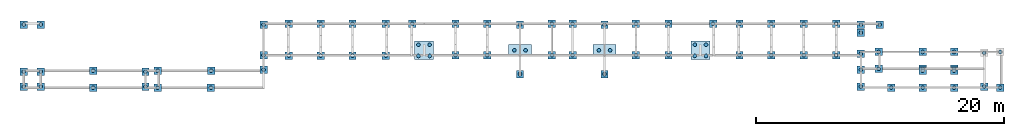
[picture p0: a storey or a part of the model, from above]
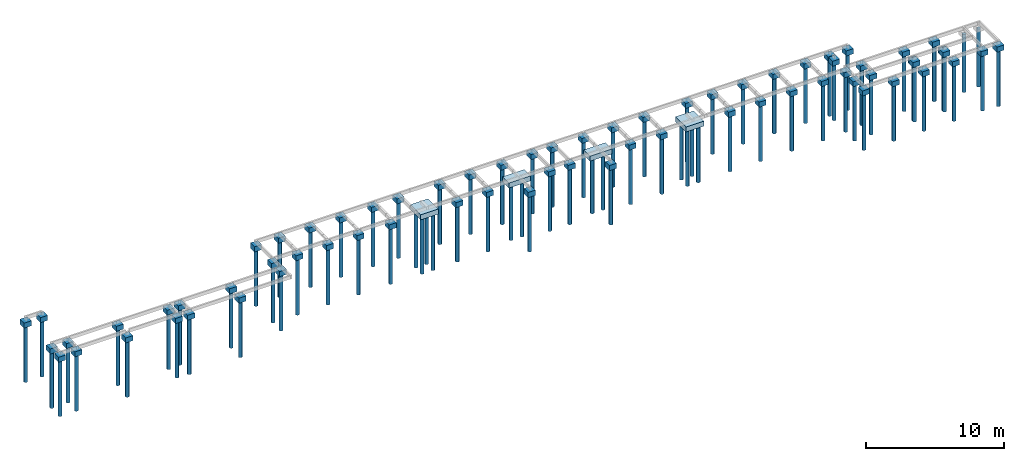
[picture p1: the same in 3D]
Properties of the parts of a building model (IFC4)

# File
Description: IFC4
Time: 2025-08-13T14:13:05
Made in: IfcPlusPlus

# IfcBuildingStorey (3)
Name | LongName | Elevation (cm)
Baldrame | Baldrame | -170
Arquibancada | Arquibancada | 0
Respalto | Respalto | 280

# IfcBeam (379)
Material: Concreto
Pset_ConcreteElementGeneral - ConcreteCover: 3 cm; ConstructionMethod: InSitu; ExposureClass: 2; StrengthClass: C-25
AltoQi_Eberick_Elemento - Elemento: Viga; Tipo: retangular; Taxa de armadura: Não calculado
AltoQi_Eberick_Padrão - Ambiente: Externo; Cobrimento: 3 cm; Classe de concreto: C-25
AltoQi_Eberick_Cargas - Cargas de parede (G2): 0; Adicional (G2): 0; Solo (S): 0; Acidental (Q): 0; Água (A): 0; Subpressão (AS): 0
Pset_BeamCommon - IsExternal: yes; LoadBearing: yes
Name | In | Seção_bw (cm) | Seção_h (cm) | Elevação (cm) | Reference
V1 | Baldrame | 14 | 30 | 0 | Viga C-25 - Seção Retangular 14 X 30
V10 | Baldrame | 14 | 30 | 0 | Viga C-25 - Seção Retangular 14 X 30
4 x V11 | Baldrame | 14 | 30 | 0 | Viga C-25 - Seção Retangular 14 X 30
6 x V12 | Baldrame | 14 | 30 | 0 | Viga C-25 - Seção Retangular 14 X 30
4 x V13 | Baldrame | 14 | 30 | 0 | Viga C-25 - Seção Retangular 14 X 30
6 x V14 | Baldrame | 14 | 30 | 0 | Viga C-25 - Seção Retangular 14 X 30
5 x V15 | Baldrame | 14 | 30 | 0 | Viga C-25 - Seção Retangular 14 X 30
V16 | Baldrame | 14 | 30 | 0 | Viga C-25 - Seção Retangular 14 X 30
V17 | Baldrame | 14 | 30 | 0 | Viga C-25 - Seção Retangular 14 X 30
V18 | Baldrame | 14 | 30 | 0 | Viga C-25 - Seção Retangular 14 X 30
V19 | Baldrame | 14 | 30 | 0 | Viga C-25 - Seção Retangular 14 X 30
6 x V2 | Baldrame | 14 | 30 | 0 | Viga C-25 - Seção Retangular 14 X 30
3 x V20 | Baldrame | 14 | 30 | 0 | Viga C-25 - Seção Retangular 14 X 30
3 x V21 | Baldrame | 19 | 30 | 0 | Viga C-25 - Seção Retangular 19 X 30
3 x V22 | Baldrame | 19 | 19 | 0 | Viga C-25 - Seção Retangular 19 X 19
3 x V23 | Baldrame | 19 | 19 | 0 | Viga C-25 - Seção Retangular 19 X 19
3 x V24 | Baldrame | 19 | 30 | 0 | Viga C-25 - Seção Retangular 19 X 30
3 x V25 | Baldrame | 19 | 30 | 0 | Viga C-25 - Seção Retangular 19 X 30
3 x V26 | Baldrame | 19 | 30 | 0 | Viga C-25 - Seção Retangular 19 X 30
3 x V27 | Baldrame | 19 | 30 | 0 | Viga C-25 - Seção Retangular 19 X 30
2 x V28 | Baldrame | 14 | 30 | 0 | Viga C-25 - Seção Retangular 14 X 30
V29 | Baldrame | 14 | 30 | 0 | Viga C-25 - Seção Retangular 14 X 30
8 x V3 | Baldrame | 14 | 30 | 0 | Viga C-25 - Seção Retangular 14 X 30
V30 | Baldrame | 14 | 30 | 0 | Viga C-25 - Seção Retangular 14 X 30
2 x V31 | Baldrame | 14 | 30 | 0 | Viga C-25 - Seção Retangular 14 X 30
3 x V32 | Baldrame | 19 | 30 | 0 | Viga C-25 - Seção Retangular 19 X 30
3 x V33 | Baldrame | 19 | 30 | 0 | Viga C-25 - Seção Retangular 19 X 30
3 x V34 | Baldrame | 19 | 30 | 0 | Viga C-25 - Seção Retangular 19 X 30
3 x V35 | Baldrame | 19 | 30 | 0 | Viga C-25 - Seção Retangular 19 X 30
3 x V36 | Baldrame | 19 | 30 | 0 | Viga C-25 - Seção Retangular 19 X 30
3 x V37 | Baldrame | 19 | 30 | 0 | Viga C-25 - Seção Retangular 19 X 30
3 x V38 | Baldrame | 19 | 30 | 0 | Viga C-25 - Seção Retangular 19 X 30
2 x V39 | Baldrame | 14 | 30 | 0 | Viga C-25 - Seção Retangular 14 X 30
6 x V4 | Baldrame | 14 | 30 | 0 | Viga C-25 - Seção Retangular 14 X 30
V40 | Baldrame | 14 | 30 | 0 | Viga C-25 - Seção Retangular 14 X 30
2 x V41 | Baldrame | 14 | 30 | 0 | Viga C-25 - Seção Retangular 14 X 30
V42 | Baldrame | 14 | 30 | 0 | Viga C-25 - Seção Retangular 14 X 30
V5 | Baldrame | 14 | 30 | 0 | Viga C-25 - Seção Retangular 14 X 30
6 x V6 | Baldrame | 14 | 30 | 0 | Viga C-25 - Seção Retangular 14 X 30
3 x V7 | Baldrame | 14 | 30 | 0 | Viga C-25 - Seção Retangular 14 X 30
6 x V8 | Baldrame | 14 | 30 | 0 | Viga C-25 - Seção Retangular 14 X 30
6 x V9 | Baldrame | 14 | 30 | 0 | Viga C-25 - Seção Retangular 14 X 30
3 x V1 | Arquibancada | 14 | 30 | 0 | Viga C-25 - Seção Retangular 14 X 30
6 x V10 | Arquibancada | 14 | 30 | 0 | Viga C-25 - Seção Retangular 14 X 30
2 x V100 | Arquibancada | 14 | 30 | 0 | Viga C-25 - Seção Retangular 14 X 30
2 x V101 | Arquibancada | 14 | 30 | 0 | Viga C-25 - Seção Retangular 14 X 30
2 x V102 | Arquibancada | 14 | 30 | 0 | Viga C-25 - Seção Retangular 14 X 30
3 x V103 | Arquibancada | 14 | 30 | 0 | Viga C-25 - Seção Retangular 14 X 30
2 x V104 | Arquibancada | 14 | 30 | 0 | Viga C-25 - Seção Retangular 14 X 30
2 x V105 | Arquibancada | 14 | 30 | 0 | Viga C-25 - Seção Retangular 14 X 30
2 x V106 | Arquibancada | 14 | 30 | 0 | Viga C-25 - Seção Retangular 14 X 30
3 x V107 | Arquibancada | 14 | 30 | 0 | Viga C-25 - Seção Retangular 14 X 30
V11 | Arquibancada | 14 | 30 | 0 | Viga C-25 - Seção Retangular 14 X 30
V12 | Arquibancada | 14 | 30 | 0 | Viga C-25 - Seção Retangular 14 X 30
V13 | Arquibancada | 14 | 30 | 0 | Viga C-25 - Seção Retangular 14 X 30
V14 | Arquibancada | 14 | 30 | 0 | Viga C-25 - Seção Retangular 14 X 30
3 x V17 | Arquibancada | 14 | 30 | 0 | Viga C-25 - Seção Retangular 14 X 30
3 x V18 | Arquibancada | 14 | 30 | 0 | Viga C-25 - Seção Retangular 14 X 30
3 x V19 | Arquibancada | 14 | 30 | 0 | Viga C-25 - Seção Retangular 14 X 30
3 x V2 | Arquibancada | 14 | 30 | 0 | Viga C-25 - Seção Retangular 14 X 30
V20 | Arquibancada | 14 | 30 | 0 | Viga C-25 - Seção Retangular 14 X 30
6 x V21 | Arquibancada | 14 | 30 | 0 | Viga C-25 - Seção Retangular 14 X 30
3 x V22 | Arquibancada | 14 | 30 | 0 | Viga C-25 - Seção Retangular 14 X 30
3 x V23 | Arquibancada | 14 | 30 | 0 | Viga C-25 - Seção Retangular 14 X 30
6 x V24 | Arquibancada | 14 | 30 | 0 | Viga C-25 - Seção Retangular 14 X 30
V25 | Arquibancada | 14 | 30 | -13 | Viga C-25 - Seção Retangular 14 X 30
V26 | Arquibancada | 14 | 30 | -13 | Viga C-25 - Seção Retangular 14 X 30
V27 | Arquibancada | 14 | 30 | -13 | Viga C-25 - Seção Retangular 14 X 30
V28 | Arquibancada | 14 | 30 | -13 | Viga C-25 - Seção Retangular 14 X 30
3 x V29 | Arquibancada | 14 | 30 | 0 | Viga C-25 - Seção Retangular 14 X 30
9 x V3 | Arquibancada | 14 | 30 | 0 | Viga C-25 - Seção Retangular 14 X 30
5 x V31 | Arquibancada | 14 | 30 | 0 | Viga C-25 - Seção Retangular 14 X 30
V32 | Arquibancada | 14 | 30 | -13 | Viga C-25 - Seção Retangular 14 X 30
V33 | Arquibancada | 14 | 30 | -13 | Viga C-25 - Seção Retangular 14 X 30
3 x V35 | Arquibancada | 14 | 30 | 0 | Viga C-25 - Seção Retangular 14 X 30
3 x V36 | Arquibancada | 14 | 30 | 0 | Viga C-25 - Seção Retangular 14 X 30
9 x V37 | Arquibancada | 14 | 30 | 0 | Viga C-25 - Seção Retangular 14 X 30
9 x V38 | Arquibancada | 14 | 30 | 0 | Viga C-25 - Seção Retangular 14 X 30
V39 | Arquibancada | 14 | 30 | 12 | Viga C-25 - Seção Retangular 14 X 30
V4 | Arquibancada | 14 | 30 | 0 | Viga C-25 - Seção Retangular 14 X 30
V40 | Arquibancada | 14 | 30 | 12 | Viga C-25 - Seção Retangular 14 X 30
5 x V41 | Arquibancada | 14 | 30 | 0 | Viga C-25 - Seção Retangular 14 X 30
2 x V42 | Arquibancada | 14 | 30 | 0 | Viga C-25 - Seção Retangular 14 X 30
3 x V43 | Arquibancada | 14 | 30 | 0 | Viga C-25 - Seção Retangular 14 X 30
3 x V44 | Arquibancada | 14 | 20 | 0 | Viga C-25 - Seção Retangular 14 X 20
3 x V45 | Arquibancada | 14 | 30 | 0 | Viga C-25 - Seção Retangular 14 X 30
3 x V46 | Arquibancada | 14 | 30 | 12 | Viga C-25 - Seção Retangular 14 X 30
V47 | Arquibancada | 14 | 30 | 12 | Viga C-25 - Seção Retangular 14 X 30
V48 | Arquibancada | 14 | 30 | 12 | Viga C-25 - Seção Retangular 14 X 30
V49 | Arquibancada | 14 | 30 | 12 | Viga C-25 - Seção Retangular 14 X 30
4 x V5 | Arquibancada | 14 | 30 | 0 | Viga C-25 - Seção Retangular 14 X 30
3 x V50 | Arquibancada | 14 | 30 | 0 | Viga C-25 - Seção Retangular 14 X 30
3 x V51 | Arquibancada | 14 | 30 | 0 | Viga C-25 - Seção Retangular 14 X 30
8 x V52 | Arquibancada | 14 | 30 | 0 | Viga C-25 - Seção Retangular 14 X 30
8 x V53 | Arquibancada | 14 | 30 | 0 | Viga C-25 - Seção Retangular 14 X 30
V54 | Arquibancada | 14 | 30 | -19 | Viga C-25 - Seção Retangular 14 X 30
V55 | Arquibancada | 14 | 30 | -6 | Viga C-25 - Seção Retangular 14 X 30
V56 | Arquibancada | 14 | 30 | -19 | Viga C-25 - Seção Retangular 14 X 30
V57 | Arquibancada | 14 | 30 | -6 | Viga C-25 - Seção Retangular 14 X 30
V58 | Arquibancada | 14 | 30 | -6 | Viga C-25 - Seção Retangular 14 X 30
V59 | Arquibancada | 14 | 30 | -6 | Viga C-25 - Seção Retangular 14 X 30
2 x V6 | Arquibancada | 14 | 30 | 0 | Viga C-25 - Seção Retangular 14 X 30
4 x V60 | Arquibancada | 14 | 30 | 0 | Viga C-25 - Seção Retangular 14 X 30
3 x V61 | Arquibancada | 14 | 30 | 0 | Viga C-25 - Seção Retangular 14 X 30
3 x V62 | Arquibancada | 14 | 30 | 0 | Viga C-25 - Seção Retangular 14 X 30
V63 | Arquibancada | 14 | 30 | -19 | Viga C-25 - Seção Retangular 14 X 30
3 x V64 | Arquibancada | 14 | 30 | 0 | Viga C-25 - Seção Retangular 14 X 30
V66 | Arquibancada | 14 | 30 | -6 | Viga C-25 - Seção Retangular 14 X 30
V67 | Arquibancada | 14 | 30 | -6 | Viga C-25 - Seção Retangular 14 X 30
V68 | Arquibancada | 14 | 30 | -19 | Viga C-25 - Seção Retangular 14 X 30
V69 | Arquibancada | 14 | 30 | -19 | Viga C-25 - Seção Retangular 14 X 30
V7 | Arquibancada | 14 | 30 | 0 | Viga C-25 - Seção Retangular 14 X 30
V70 | Arquibancada | 14 | 30 | -19 | Viga C-25 - Seção Retangular 14 X 30
V71 | Arquibancada | 14 | 30 | -19 | Viga C-25 - Seção Retangular 14 X 30
V72 | Arquibancada | 14 | 30 | -19 | Viga C-25 - Seção Retangular 14 X 30
V73 | Arquibancada | 14 | 30 | -19 | Viga C-25 - Seção Retangular 14 X 30
V74 | Arquibancada | 14 | 30 | 0 | Viga C-25 - Seção Retangular 14 X 30
V75 | Arquibancada | 14 | 30 | -19 | Viga C-25 - Seção Retangular 14 X 30
V76 | Arquibancada | 14 | 30 | -19 | Viga C-25 - Seção Retangular 14 X 30
V77 | Arquibancada | 14 | 30 | 0 | Viga C-25 - Seção Retangular 14 X 30
V78 | Arquibancada | 14 | 30 | 0 | Viga C-25 - Seção Retangular 14 X 30
V8 | Arquibancada | 14 | 30 | 0 | Viga C-25 - Seção Retangular 14 X 30
V81 | Arquibancada | 14 | 30 | -19 | Viga C-25 - Seção Retangular 14 X 30
3 x V82 | Arquibancada | 14 | 30 | 0 | Viga C-25 - Seção Retangular 14 X 30
V83 | Arquibancada | 14 | 30 | -19 | Viga C-25 - Seção Retangular 14 X 30
V84 | Arquibancada | 14 | 30 | -19 | Viga C-25 - Seção Retangular 14 X 30
2 x V85 | Arquibancada | 14 | 30 | 0 | Viga C-25 - Seção Retangular 14 X 30
2 x V86 | Arquibancada | 14 | 30 | 0 | Viga C-25 - Seção Retangular 14 X 30
2 x V87 | Arquibancada | 14 | 30 | 0 | Viga C-25 - Seção Retangular 14 X 30
V88 | Arquibancada | 14 | 30 | 0 | Viga C-25 - Seção Retangular 14 X 30
3 x V89 | Arquibancada | 14 | 30 | 0 | Viga C-25 - Seção Retangular 14 X 30
2 x V9 | Arquibancada | 14 | 30 | 0 | Viga C-25 - Seção Retangular 14 X 30
2 x V90 | Arquibancada | 14 | 30 | 0 | Viga C-25 - Seção Retangular 14 X 30
2 x V91 | Arquibancada | 14 | 30 | 0 | Viga C-25 - Seção Retangular 14 X 30
2 x V92 | Arquibancada | 14 | 30 | 0 | Viga C-25 - Seção Retangular 14 X 30
2 x V93 | Arquibancada | 14 | 30 | 0 | Viga C-25 - Seção Retangular 14 X 30
2 x V94 | Arquibancada | 14 | 30 | 0 | Viga C-25 - Seção Retangular 14 X 30
3 x V95 | Arquibancada | 14 | 30 | 0 | Viga C-25 - Seção Retangular 14 X 30
2 x V96 | Arquibancada | 14 | 30 | 0 | Viga C-25 - Seção Retangular 14 X 30
2 x V97 | Arquibancada | 14 | 30 | 0 | Viga C-25 - Seção Retangular 14 X 30
2 x V98 | Arquibancada | 14 | 30 | 0 | Viga C-25 - Seção Retangular 14 X 30
3 x V99 | Arquibancada | 14 | 30 | 0 | Viga C-25 - Seção Retangular 14 X 30
3 x V1 | Respalto | 14 | 30 | 0 | Viga C-25 - Seção Retangular 14 X 30
3 x V2 | Respalto | 14 | 30 | 0 | Viga C-25 - Seção Retangular 14 X 30
2 x V3 | Respalto | 14 | 30 | 0 | Viga C-25 - Seção Retangular 14 X 30
V4 | Respalto | 14 | 30 | 0 | Viga C-25 - Seção Retangular 14 X 30
V5 | Respalto | 14 | 30 | 0 | Viga C-25 - Seção Retangular 14 X 30
2 x V6 | Respalto | 14 | 30 | 0 | Viga C-25 - Seção Retangular 14 X 30

# IfcColumn (193)
Material: Concreto
Pset_ConcreteElementGeneral - ConcreteCover: 3 cm; ConstructionMethod: InSitu; ExposureClass: 2; StrengthClass: C-25
AltoQi_Eberick_Elemento - Elemento: Pilar; Tipo: retangular; Taxa de armadura: Não calculado; Taxa de compressão bruta: Não calculado; Taxa de compressão homogeneizada: Não calculado
AltoQi_Eberick_Padrão - Ambiente: Externo; Cobrimento: 3 cm; Classe de concreto: C-25
Pset_ColumnCommon - IsExternal: yes; LoadBearing: yes
Name | In | Seção_b (cm) | Seção_h (cm) | Elevação (cm) | Reference
P1 | Baldrame | 14 | 30 | 0 | Pilar C-25 - Retangular 14x30
P10 | Baldrame | 14 | 30 | 0 | Pilar C-25 - Retangular 14x30
P100 | Baldrame | 14 | 30 | 0 | Pilar C-25 - Retangular 14x30
P101 | Baldrame | 14 | 30 | 0 | Pilar C-25 - Retangular 14x30
P102 | Baldrame | 14 | 30 | 0 | Pilar C-25 - Retangular 14x30
P103 | Baldrame | 14 | 30 | 0 | Pilar C-25 - Retangular 14x30
P104 | Baldrame | 14 | 30 | 0 | Pilar C-25 - Retangular 14x30
P105 | Baldrame | 14 | 30 | 0 | Pilar C-25 - Retangular 14x30
P106 | Baldrame | 14 | 30 | -19 | Pilar C-25 - Retangular 14x30
P11 | Baldrame | 14 | 30 | 0 | Pilar C-25 - Retangular 14x30
P12 | Baldrame | 14 | 30 | 0 | Pilar C-25 - Retangular 14x30
P13 | Baldrame | 14 | 30 | 0 | Pilar C-25 - Retangular 14x30
P14 | Baldrame | 14 | 30 | 0 | Pilar C-25 - Retangular 14x30
P15 | Baldrame | 14 | 30 | 0 | Pilar C-25 - Retangular 14x30
P16 | Baldrame | 14 | 30 | 0 | Pilar C-25 - Retangular 14x30
P17 | Baldrame | 14 | 30 | 0 | Pilar C-25 - Retangular 14x30
P18 | Baldrame | 14 | 30 | 0 | Pilar C-25 - Retangular 14x30
P19 | Baldrame | 14 | 30 | 0 | Pilar C-25 - Retangular 14x30
P2 | Baldrame | 14 | 30 | 0 | Pilar C-25 - Retangular 14x30
P20 | Baldrame | 14 | 30 | 0 | Pilar C-25 - Retangular 14x30
P21 | Baldrame | 19 | 19 | 0 | Pilar C-25 - Retangular 19x19
P22 | Baldrame | 14 | 30 | 0 | Pilar C-25 - Retangular 14x30
P23 | Baldrame | 14 | 30 | 0 | Pilar C-25 - Retangular 14x30
P3 | Baldrame | 14 | 30 | 0 | Pilar C-25 - Retangular 14x30
P38 | Baldrame | 14 | 30 | 0 | Pilar C-25 - Retangular 14x30
P4 | Baldrame | 14 | 30 | 0 | Pilar C-25 - Retangular 14x30
P44 | Baldrame | 20 | 93 | 0 | Pilar C-25 - Retangular 20x93
P47 | Baldrame | 14 | 93 | 0 | Pilar C-25 - Retangular 14x93
P48 | Baldrame | 14 | 93 | 0 | Pilar C-25 - Retangular 14x93
P5 | Baldrame | 14 | 30 | 0 | Pilar C-25 - Retangular 14x30
P51 | Baldrame | 20 | 93 | 0 | Pilar C-25 - Retangular 20x93
P57 | Baldrame | 14 | 30 | 0 | Pilar C-25 - Retangular 14x30
P58 | Baldrame | 19 | 30 | 0 | Pilar C-25 - Retangular 19x30
P59 | Baldrame | 19 | 30 | 0 | Pilar C-25 - Retangular 19x30
P6 | Baldrame | 14 | 30 | 0 | Pilar C-25 - Retangular 14x30
P60 | Baldrame | 19 | 30 | 0 | Pilar C-25 - Retangular 19x30
P61 | Baldrame | 19 | 30 | 0 | Pilar C-25 - Retangular 19x30
P62 | Baldrame | 14 | 30 | 0 | Pilar C-25 - Retangular 14x30
P63 | Baldrame | 14 | 30 | 0 | Pilar C-25 - Retangular 14x30
P64 | Baldrame | 14 | 30 | 0 | Pilar C-25 - Retangular 14x30
P65 | Baldrame | 14 | 30 | 0 | Pilar C-25 - Retangular 14x30
P66 | Baldrame | 14 | 30 | 0 | Pilar C-25 - Retangular 14x30
P67 | Baldrame | 14 | 30 | 0 | Pilar C-25 - Retangular 14x30
P68 | Baldrame | 14 | 30 | 0 | Pilar C-25 - Retangular 14x30
P69 | Baldrame | 14 | 30 | 0 | Pilar C-25 - Retangular 14x30
P7 | Baldrame | 14 | 30 | 0 | Pilar C-25 - Retangular 14x30
P70 | Baldrame | 14 | 30 | 0 | Pilar C-25 - Retangular 14x30
P71 | Baldrame | 19 | 19 | 0 | Pilar C-25 - Retangular 19x19
P72 | Baldrame | 14 | 40 | 0 | Pilar C-25 - Retangular 14x40
P73 | Baldrame | 14 | 30 | 0 | Pilar C-25 - Retangular 14x30
P74 | Baldrame | 14 | 30 | 0 | Pilar C-25 - Retangular 14x30
P75 | Baldrame | 14 | 30 | 0 | Pilar C-25 - Retangular 14x30
P76 | Baldrame | 14 | 30 | 0 | Pilar C-25 - Retangular 14x30
P77 | Baldrame | 14 | 30 | 0 | Pilar C-25 - Retangular 14x30
P78 | Baldrame | 14 | 30 | 0 | Pilar C-25 - Retangular 14x30
P79 | Baldrame | 14 | 30 | 0 | Pilar C-25 - Retangular 14x30
P8 | Baldrame | 14 | 30 | 0 | Pilar C-25 - Retangular 14x30
P80 | Baldrame | 14 | 30 | 0 | Pilar C-25 - Retangular 14x30
P81 | Baldrame | 14 | 30 | 0 | Pilar C-25 - Retangular 14x30
P82 | Baldrame | 14 | 30 | 0 | Pilar C-25 - Retangular 14x30
P83 | Baldrame | 14 | 30 | 0 | Pilar C-25 - Retangular 14x30
P84 | Baldrame | 14 | 30 | 0 | Pilar C-25 - Retangular 14x30
P85 | Baldrame | 14 | 30 | 0 | Pilar C-25 - Retangular 14x30
P86 | Baldrame | 14 | 30 | 0 | Pilar C-25 - Retangular 14x30
P87 | Baldrame | 14 | 29 | 0 | Pilar C-25 - Retangular 14x29
P88 | Baldrame | 14 | 30 | 0 | Pilar C-25 - Retangular 14x30
P89 | Baldrame | 14 | 30 | 0 | Pilar C-25 - Retangular 14x30
P9 | Baldrame | 14 | 30 | 0 | Pilar C-25 - Retangular 14x30
P90 | Baldrame | 14 | 30 | 0 | Pilar C-25 - Retangular 14x30
P91 | Baldrame | 14 | 30 | 0 | Pilar C-25 - Retangular 14x30
P92 | Baldrame | 14 | 30 | 0 | Pilar C-25 - Retangular 14x30
P93 | Baldrame | 14 | 30 | 0 | Pilar C-25 - Retangular 14x30
P94 | Baldrame | 14 | 30 | 0 | Pilar C-25 - Retangular 14x30
P96 | Baldrame | 14 | 30 | 0 | Pilar C-25 - Retangular 14x30
P97 | Baldrame | 14 | 30 | 0 | Pilar C-25 - Retangular 14x30
P98 | Baldrame | 14 | 30 | 0 | Pilar C-25 - Retangular 14x30
P10 | Arquibancada | 14 | 30 | 0 | Pilar C-25 - Retangular 14x30
P100 | Arquibancada | 14 | 30 | 0 | Pilar C-25 - Retangular 14x30
P101 | Arquibancada | 14 | 30 | 0 | Pilar C-25 - Retangular 14x30
P102 | Arquibancada | 14 | 30 | 0 | Pilar C-25 - Retangular 14x30
P103 | Arquibancada | 14 | 30 | 0 | Pilar C-25 - Retangular 14x30
P104 | Arquibancada | 14 | 30 | 12 | Pilar C-25 - Retangular 14x30
P105 | Arquibancada | 14 | 30 | 12 | Pilar C-25 - Retangular 14x30
P106 | Arquibancada | 14 | 30 | -10 | Pilar C-25 - Retangular 14x30
P107 | Arquibancada | 14 | 30 | 0 | Pilar C-25 - Retangular 14x30
P108 | Arquibancada | 14 | 30 | 0 | Pilar C-25 - Retangular 14x30
P109 | Arquibancada | 14 | 30 | -35 | Pilar C-25 - Retangular 14x30
P11 | Arquibancada | 14 | 30 | 0 | Pilar C-25 - Retangular 14x30
P12 | Arquibancada | 14 | 30 | 0 | Pilar C-25 - Retangular 14x30
P13 | Arquibancada | 14 | 30 | 0 | Pilar C-25 - Retangular 14x30
P14 | Arquibancada | 14 | 30 | 0 | Pilar C-25 - Retangular 14x30
P15 | Arquibancada | 14 | 30 | 0 | Pilar C-25 - Retangular 14x30
P16 | Arquibancada | 14 | 30 | 0 | Pilar C-25 - Retangular 14x30
P17 | Arquibancada | 14 | 30 | 0 | Pilar C-25 - Retangular 14x30
P18 | Arquibancada | 14 | 30 | 0 | Pilar C-25 - Retangular 14x30
P19 | Arquibancada | 14 | 30 | 0 | Pilar C-25 - Retangular 14x30
P20 | Arquibancada | 14 | 30 | 0 | Pilar C-25 - Retangular 14x30
P21 | Arquibancada | 19 | 19 | 0 | Pilar C-25 - Retangular 19x19
P22 | Arquibancada | 14 | 30 | 0 | Pilar C-25 - Retangular 14x30
P24 | Arquibancada | 19 | 19 | 0 | Pilar C-25 - Retangular 19x19
P25 | Arquibancada | 20 | 20 | 0 | Pilar C-25 - Retangular 20x20
P26 | Arquibancada | 19 | 19 | 0 | Pilar C-25 - Retangular 19x19
P27 | Arquibancada | 19 | 19 | 0 | Pilar C-25 - Retangular 19x19
P28 | Arquibancada | 19 | 19 | 0 | Pilar C-25 - Retangular 19x19
P29 | Arquibancada | 19 | 19 | 0 | Pilar C-25 - Retangular 19x19
P3 | Arquibancada | 14 | 30 | 0 | Pilar C-25 - Retangular 14x30
P30 | Arquibancada | 19 | 19 | 0 | Pilar C-25 - Retangular 19x19
P31 | Arquibancada | 19 | 19 | 0 | Pilar C-25 - Retangular 19x19
P32 | Arquibancada | 19 | 19 | 0 | Pilar C-25 - Retangular 19x19
P33 | Arquibancada | 19 | 19 | 0 | Pilar C-25 - Retangular 19x19
P34 | Arquibancada | 19 | 19 | 0 | Pilar C-25 - Retangular 19x19
P35 | Arquibancada | 19 | 19 | 0 | Pilar C-25 - Retangular 19x19
P36 | Arquibancada | 19 | 19 | 0 | Pilar C-25 - Retangular 19x19
P37 | Arquibancada | 19 | 19 | 0 | Pilar C-25 - Retangular 19x19
P38 | Arquibancada | 14 | 30 | 0 | Pilar C-25 - Retangular 14x30
P39 | Arquibancada | 19 | 19 | 0 | Pilar C-25 - Retangular 19x19
P4 | Arquibancada | 14 | 30 | 0 | Pilar C-25 - Retangular 14x30
P40 | Arquibancada | 20 | 20 | 0 | Pilar C-25 - Retangular 20x20
P41 | Arquibancada | 19 | 19 | 0 | Pilar C-25 - Retangular 19x19
P42 | Arquibancada | 19 | 19 | 0 | Pilar C-25 - Retangular 19x19
P43 | Arquibancada | 19 | 19 | 0 | Pilar C-25 - Retangular 19x19
P44 | Arquibancada | 20 | 93 | 0 | Pilar C-25 - Retangular 20x93
P45 | Arquibancada | 19 | 19 | 0 | Pilar C-25 - Retangular 19x19
P46 | Arquibancada | 19 | 19 | 0 | Pilar C-25 - Retangular 19x19
P47 | Arquibancada | 14 | 93 | 0 | Pilar C-25 - Retangular 14x93
P48 | Arquibancada | 14 | 93 | 0 | Pilar C-25 - Retangular 14x93
P49 | Arquibancada | 19 | 19 | 0 | Pilar C-25 - Retangular 19x19
P5 | Arquibancada | 14 | 30 | 0 | Pilar C-25 - Retangular 14x30
P50 | Arquibancada | 19 | 19 | 0 | Pilar C-25 - Retangular 19x19
P51 | Arquibancada | 20 | 93 | 0 | Pilar C-25 - Retangular 20x93
P52 | Arquibancada | 19 | 19 | 0 | Pilar C-25 - Retangular 19x19
P53 | Arquibancada | 19 | 19 | 0 | Pilar C-25 - Retangular 19x19
P54 | Arquibancada | 19 | 19 | 0 | Pilar C-25 - Retangular 19x19
P55 | Arquibancada | 19 | 19 | 0 | Pilar C-25 - Retangular 19x19
P56 | Arquibancada | 19 | 19 | 0 | Pilar C-25 - Retangular 19x19
P57 | Arquibancada | 14 | 30 | 0 | Pilar C-25 - Retangular 14x30
P58 | Arquibancada | 19 | 30 | 0 | Pilar C-25 - Retangular 19x30
P59 | Arquibancada | 19 | 30 | 0 | Pilar C-25 - Retangular 19x30
P6 | Arquibancada | 14 | 30 | 0 | Pilar C-25 - Retangular 14x30
P60 | Arquibancada | 19 | 30 | 0 | Pilar C-25 - Retangular 19x30
P61 | Arquibancada | 19 | 30 | 0 | Pilar C-25 - Retangular 19x30
P62 | Arquibancada | 14 | 30 | 0 | Pilar C-25 - Retangular 14x30
P63 | Arquibancada | 14 | 30 | 0 | Pilar C-25 - Retangular 14x30
P64 | Arquibancada | 14 | 30 | 0 | Pilar C-25 - Retangular 14x30
P65 | Arquibancada | 14 | 30 | 0 | Pilar C-25 - Retangular 14x30
P66 | Arquibancada | 14 | 30 | 0 | Pilar C-25 - Retangular 14x30
P67 | Arquibancada | 14 | 30 | 0 | Pilar C-25 - Retangular 14x30
P68 | Arquibancada | 14 | 30 | 0 | Pilar C-25 - Retangular 14x30
P69 | Arquibancada | 14 | 30 | 0 | Pilar C-25 - Retangular 14x30
P7 | Arquibancada | 14 | 30 | 0 | Pilar C-25 - Retangular 14x30
P70 | Arquibancada | 14 | 30 | 0 | Pilar C-25 - Retangular 14x30
P71 | Arquibancada | 19 | 19 | 0 | Pilar C-25 - Retangular 19x19
P72 | Arquibancada | 14 | 40 | 0 | Pilar C-25 - Retangular 14x40
P73 | Arquibancada | 14 | 30 | -19 | Pilar C-25 - Retangular 14x30
P74 | Arquibancada | 14 | 30 | 0 | Pilar C-25 - Retangular 14x30
P75 | Arquibancada | 14 | 30 | -10 | Pilar C-25 - Retangular 14x30
P76 | Arquibancada | 14 | 30 | 12 | Pilar C-25 - Retangular 14x30
P77 | Arquibancada | 14 | 30 | 12 | Pilar C-25 - Retangular 14x30
P78 | Arquibancada | 14 | 30 | -6 | Pilar C-25 - Retangular 14x30
P79 | Arquibancada | 14 | 30 | -6 | Pilar C-25 - Retangular 14x30
P8 | Arquibancada | 14 | 30 | 0 | Pilar C-25 - Retangular 14x30
P80 | Arquibancada | 14 | 30 | -10 | Pilar C-25 - Retangular 14x30
P81 | Arquibancada | 14 | 30 | -13 | Pilar C-25 - Retangular 14x30
P82 | Arquibancada | 14 | 30 | -13 | Pilar C-25 - Retangular 14x30
P83 | Arquibancada | 14 | 30 | -35 | Pilar C-25 - Retangular 14x30
P84 | Arquibancada | 14 | 30 | 0 | Pilar C-25 - Retangular 14x30
P85 | Arquibancada | 14 | 30 | 0 | Pilar C-25 - Retangular 14x30
P86 | Arquibancada | 14 | 30 | 0 | Pilar C-25 - Retangular 14x30
P87 | Arquibancada | 14 | 29 | 0 | Pilar C-25 - Retangular 14x29
P88 | Arquibancada | 14 | 30 | -19 | Pilar C-25 - Retangular 14x30
P89 | Arquibancada | 14 | 30 | 0 | Pilar C-25 - Retangular 14x30
P9 | Arquibancada | 14 | 30 | 0 | Pilar C-25 - Retangular 14x30
P90 | Arquibancada | 14 | 30 | 0 | Pilar C-25 - Retangular 14x30
P91 | Arquibancada | 14 | 30 | -10 | Pilar C-25 - Retangular 14x30
P92 | Arquibancada | 14 | 30 | 0 | Pilar C-25 - Retangular 14x30
P93 | Arquibancada | 14 | 30 | -6 | Pilar C-25 - Retangular 14x30
P94 | Arquibancada | 14 | 30 | -6 | Pilar C-25 - Retangular 14x30
P96 | Arquibancada | 14 | 30 | -13 | Pilar C-25 - Retangular 14x30
P97 | Arquibancada | 14 | 30 | -13 | Pilar C-25 - Retangular 14x30
P98 | Arquibancada | 14 | 30 | -35 | Pilar C-25 - Retangular 14x30
P99 | Arquibancada | 14 | 30 | 0 | Pilar C-25 - Retangular 14x30
P11 | Respalto | 14 | 30 | 0 | Pilar C-25 - Retangular 14x30
P12 | Respalto | 14 | 30 | 0 | Pilar C-25 - Retangular 14x30
P13 | Respalto | 14 | 30 | 0 | Pilar C-25 - Retangular 14x30
P14 | Respalto | 14 | 30 | 0 | Pilar C-25 - Retangular 14x30
P44 | Respalto | 20 | 93 | 0 | Pilar C-25 - Retangular 20x93
P47 | Respalto | 14 | 93 | 0 | Pilar C-25 - Retangular 14x93
P48 | Respalto | 14 | 93 | 0 | Pilar C-25 - Retangular 14x93
P51 | Respalto | 20 | 93 | 0 | Pilar C-25 - Retangular 20x93
P64 | Respalto | 14 | 30 | 0 | Pilar C-25 - Retangular 14x30
P65 | Respalto | 14 | 30 | 0 | Pilar C-25 - Retangular 14x30
P85 | Respalto | 14 | 30 | 0 | Pilar C-25 - Retangular 14x30
P86 | Respalto | 14 | 30 | 0 | Pilar C-25 - Retangular 14x30

# IfcFooting (76)
In: Baldrame
Material: Concreto
Pset_ConcreteElementGeneral - ConcreteCover: 4.5 cm; ConstructionMethod: InSitu; ExposureClass: 2; StrengthClass: C-25
AltoQi_Eberick_Elemento - Elemento: Bloco; Seção_LB: Não calculado; Seção_LH: Não calculado
AltoQi_Eberick_Padrão - Cobrimento: 4.5 cm; Classe de concreto: C-25
Pset_PileCommon - Reference: Estaca circular R30 - Concreto C-25
Pset_FootingCommon - Reference: Bloco C-25
Name | Tipo | Elevação (cm)
P1 | 1 | 0
P10 | 1 | 0
P100 | 1 | 0
P101 | 1 | 0
P102 | 1 | 0
P103 | 1 | 0
P104 | 1 | 0
P105 | 1 | 0
P106 | 1 | -19
P11 | 1 | 0
P12 | 1 | 0
P13 | 1 | 0
P14 | 1 | 0
P15 | 1 | 0
P16 | 1 | 0
P17 | 1 | 0
P18 | 1 | 0
P19 | 1 | 0
P2 | 1 | 0
P20 | 1 | 0
P21 | 1 | 0
P22 | 1 | 0
P23 | 1 | 0
P3 | 1 | 0
P38 | 1 | 0
P4 | 1 | 0
P44 | 4 RET | 0
P47 | 2 | 0
P48 | 2 | 0
P5 | 1 | 0
P51 | 4 RET | 0
P57 | 1 | 0
P58 | 1 | 0
P59 | 1 | 0
P6 | 1 | 0
P60 | 1 | 0
P61 | 1 | 0
P62 | 1 | 0
P63 | 1 | 0
P64 | 1 | 0
P65 | 1 | 0
P66 | 1 | 0
P67 | 1 | 0
P68 | 1 | 0
P69 | 1 | 0
P7 | 1 | 0
P70 | 1 | 0
P71 | 1 | 0
P72 | 1 | 0
P73 | 1 | 0
P74 | 1 | 0
P75 | 1 | 0
P76 | 1 | 0
P77 | 1 | 0
P78 | 1 | 0
P79 | 1 | 0
P8 | 1 | 0
P80 | 1 | 0
P81 | 1 | 0
P82 | 1 | 0
P83 | 1 | 0
P84 | 1 | 0
P85 | 1 | 0
P86 | 1 | 0
P87 | 1 | 0
P88 | 1 | 0
P89 | 1 | 0
P9 | 1 | 0
P90 | 1 | 0
P91 | 1 | 0
P92 | 1 | 0
P93 | 1 | 0
P94 | 1 | 0
P96 | 1 | 0
P97 | 1 | 0
P98 | 1 | 0

# IfcPile (84)
In: Baldrame
Material: Concreto
Pset_ConcreteElementGeneral - ConcreteCover: 4.5 cm; ConstructionMethod: InSitu; ExposureClass: 2; StrengthClass: C-25
AltoQi_Eberick_Elemento - Elemento: Bloco; Seção_LB: Não calculado; Seção_LH: Não calculado
AltoQi_Eberick_Padrão - Cobrimento: 4.5 cm; Classe de concreto: C-25
Pset_PileCommon - Reference: Estaca circular R30 - Concreto C-25
Pset_FootingCommon - Reference: Bloco C-25
Name | Tipo | Elevação (cm)
E1-1 | 1 | 0
E10-1 | 1 | 0
E100-1 | 1 | 0
E101-1 | 1 | 0
E102-1 | 1 | 0
E103-1 | 1 | 0
E104-1 | 1 | 0
E105-1 | 1 | 0
E106-1 | 1 | -19
E11-1 | 1 | 0
E12-1 | 1 | 0
E13-1 | 1 | 0
E14-1 | 1 | 0
E15-1 | 1 | 0
E16-1 | 1 | 0
E17-1 | 1 | 0
E18-1 | 1 | 0
E19-1 | 1 | 0
E2-1 | 1 | 0
E20-1 | 1 | 0
E21-1 | 1 | 0
E22-1 | 1 | 0
E23-1 | 1 | 0
E3-1 | 1 | 0
E38-1 | 1 | 0
E4-1 | 1 | 0
E44-1 | 4 RET | 0
E44-2 | 4 RET | 0
E44-3 | 4 RET | 0
E44-4 | 4 RET | 0
E47-1 | 2 | 0
E47-2 | 2 | 0
E48-1 | 2 | 0
E48-2 | 2 | 0
E5-1 | 1 | 0
E51-1 | 4 RET | 0
E51-2 | 4 RET | 0
E51-3 | 4 RET | 0
E51-4 | 4 RET | 0
E57-1 | 1 | 0
E58-1 | 1 | 0
E59-1 | 1 | 0
E6-1 | 1 | 0
E60-1 | 1 | 0
E61-1 | 1 | 0
E62-1 | 1 | 0
E63-1 | 1 | 0
E64-1 | 1 | 0
E65-1 | 1 | 0
E66-1 | 1 | 0
E67-1 | 1 | 0
E68-1 | 1 | 0
E69-1 | 1 | 0
E7-1 | 1 | 0
E70-1 | 1 | 0
E71-1 | 1 | 0
E72-1 | 1 | 0
E73-1 | 1 | 0
E74-1 | 1 | 0
E75-1 | 1 | 0
E76-1 | 1 | 0
E77-1 | 1 | 0
E78-1 | 1 | 0
E79-1 | 1 | 0
E8-1 | 1 | 0
E80-1 | 1 | 0
E81-1 | 1 | 0
E82-1 | 1 | 0
E83-1 | 1 | 0
E84-1 | 1 | 0
E85-1 | 1 | 0
E86-1 | 1 | 0
E87-1 | 1 | 0
E88-1 | 1 | 0
E89-1 | 1 | 0
E9-1 | 1 | 0
E90-1 | 1 | 0
E91-1 | 1 | 0
E92-1 | 1 | 0
E93-1 | 1 | 0
E94-1 | 1 | 0
E96-1 | 1 | 0
E97-1 | 1 | 0
E98-1 | 1 | 0

# IfcRampFlight (6)
In: Arquibancada
Material: Concreto
Pset_ConcreteElementGeneral - ConcreteCover: 3 cm; ConstructionMethod: InSitu; ExposureClass: 2; StrengthClass: C-25
AltoQi_Eberick_Elemento - Espessura: 11 cm
AltoQi_Eberick_Padrão - Ambiente: Contato com solo; Cobrimento: 3 cm; Classe de concreto: C-25
AltoQi_Eberick_Cargas - Adicional (G2): 0; Solo (S): 0; Acidental (Q): 300; Água (A): 0; Subpressão (AS): 0
Pset_RampFlightCommon - Reference: Rampa Maciça - h=11cm
Name | Elemento | Tipo | Revestimento (G2)
LE13 | Escada | Rampa | 154.5 | AltoQi_Eberick_Elemento - Piso: 0 cm; Espelho: 0 cm; Primeira_face: 0 cm
R1 | Rampa | Maciça | 155
R2 | Rampa | Maciça | 155
R3 | Rampa | Maciça | 155
R4 | Rampa | Maciça | 156
R5 | Rampa | Maciça | 157

# IfcSlab (36)
Material: Concreto
Pset_ConcreteElementGeneral - ConstructionMethod: InSitu; ExposureClass: 2; StrengthClass: C-25
AltoQi_Eberick_Padrão - Classe de concreto: C-25
AltoQi_Eberick_Cargas - Adicional (G2): 0; Solo (S): 0; Água (A): 0; Subpressão (AS): 0
Pset_SlabCommon - LoadBearing: yes; IsExternal: yes; PitchAngle: 0 rad
Name | In | PredefinedType | ConcreteCover (cm) = Cobrimento (cm) | Elemento | Tipo | Elevação (cm) | Espessura (cm) | Ambiente | Revestimento (G2) | Acidental (Q) | Reference
L1 | Arquibancada | FLOOR | 4.5 | Radier | Maciça | 0 | 11 | Contato com solo | 50 | 150 | Laje de fundação C-25 - h=11cm
L2 | Arquibancada | FLOOR | 4.5 | Radier | Maciça | 0 | 11 | Contato com solo | 50 | 250 | Laje de fundação C-25 - h=11cm
L3 | Arquibancada | FLOOR | 4.5 | Radier | Maciça | 0 | 11 | Contato com solo | 50 | 150 | Laje de fundação C-25 - h=11cm
L6 | Arquibancada | FLOOR | 2.5 | Laje | Pré-moldada | -13 | 12 | Externo | 50 | 0 | Laje Pré-moldada - h=12cm
LE10 | Arquibancada | LANDING | 2.5 | Patamar de escada | Maciça | 0 | 11 | Externo | 154.5 | 400 | Patamar de escada C-25 - h=11cm
LE12 | Arquibancada | LANDING | 2.5 | Patamar de escada | Maciça | -19 | 11 | Externo | 154.5 | 300 | Patamar de escada C-25 - h=11cm
LE19 | Arquibancada | LANDING | 2.5 | Patamar de escada | Maciça | 0 | 11 | Externo | 154.5 | 300 | Patamar de escada C-25 - h=11cm
LE2 | Arquibancada | LANDING | 2.5 | Patamar de escada | Maciça | -6 | 11 | Externo | 0 | 0 | Patamar de escada C-25 - h=11cm
LE21 | Arquibancada | LANDING | 2.5 | Patamar de escada | Maciça | 0 | 11 | Externo | 154.5 | 300 | Patamar de escada C-25 - h=11cm
LE23 | Arquibancada | LANDING | 2.5 | Patamar de escada | Maciça | 0 | 11 | Externo | 154.5 | 300 | Patamar de escada C-25 - h=11cm
LE24 | Arquibancada | LANDING | 2.5 | Patamar de escada | Maciça | 0 | 11 | Externo | 154.5 | 300 | Patamar de escada C-25 - h=11cm
LE25 | Arquibancada | LANDING | 2.5 | Patamar de escada | Maciça | 0 | 11 | Externo | 154.5 | 300 | Patamar de escada C-25 - h=11cm
LE26 | Arquibancada | LANDING | 2.5 | Patamar de escada | Maciça | 0 | 11 | Externo | 154.5 | 300 | Patamar de escada C-25 - h=11cm
LE29 | Arquibancada | LANDING | 2.5 | Patamar de escada | Maciça | 0 | 11 | Externo | 154.5 | 300 | Patamar de escada C-25 - h=11cm
LE30 | Arquibancada | LANDING | 2.5 | Patamar de escada | Maciça | 0 | 11 | Externo | 154.5 | 300 | Patamar de escada C-25 - h=11cm
LE32 | Arquibancada | LANDING | 2.5 | Patamar de escada | Maciça | 0 | 11 | Externo | 154.5 | 300 | Patamar de escada C-25 - h=11cm
LE35 | Arquibancada | LANDING | 2.5 | Patamar de escada | Maciça | 0 | 11 | Externo | 154.5 | 400 | Patamar de escada C-25 - h=11cm
LE36 | Arquibancada | LANDING | 2.5 | Patamar de escada | Maciça | 0 | 11 | Externo | 154.5 | 300 | Patamar de escada C-25 - h=11cm
LE37 | Arquibancada | LANDING | 2.5 | Patamar de escada | Maciça | 0 | 11 | Externo | 154.5 | 400 | Patamar de escada C-25 - h=11cm
LE38 | Arquibancada | LANDING | 2.5 | Patamar de escada | Maciça | 0 | 11 | Externo | 154.5 | 400 | Patamar de escada C-25 - h=11cm
LE39 | Arquibancada | LANDING | 2.5 | Patamar de escada | Maciça | 0 | 11 | Externo | 154.5 | 300 | Patamar de escada C-25 - h=11cm
LE40 | Arquibancada | LANDING | 2.5 | Patamar de escada | Maciça | 0 | 11 | Externo | 154.5 | 300 | Patamar de escada C-25 - h=11cm
LE44 | Arquibancada | LANDING | 2.5 | Patamar de escada | Maciça | 0 | 11 | Externo | 30 | 400 | Patamar de escada C-25 - h=11cm
LE46 | Arquibancada | LANDING | 2.5 | Patamar de escada | Maciça | 0 | 11 | Externo | 30 | 400 | Patamar de escada C-25 - h=11cm
LE47 | Arquibancada | LANDING | 2.5 | Patamar de escada | Maciça | 0 | 11 | Externo | 30 | 400 | Patamar de escada C-25 - h=11cm
LE49 | Arquibancada | LANDING | 2.5 | Patamar de escada | Maciça | 0 | 11 | Externo | 30 | 400 | Patamar de escada C-25 - h=11cm
LE5 | Arquibancada | LANDING | 2.5 | Patamar de escada | Maciça | 0 | 11 | Externo | 154.5 | 400 | Patamar de escada C-25 - h=11cm
LE50 | Arquibancada | LANDING | 2.5 | Patamar de escada | Maciça | 0 | 11 | Externo | 154.5 | 300 | Patamar de escada C-25 - h=11cm
LE52 | Arquibancada | LANDING | 2.5 | Patamar de escada | Maciça | 0 | 11 | Externo | 154.5 | 300 | Patamar de escada C-25 - h=11cm
LE54 | Arquibancada | LANDING | 2.5 | Patamar de escada | Maciça | 0 | 11 | Externo | 154.5 | 300 | Patamar de escada C-25 - h=11cm
LE56 | Arquibancada | LANDING | 2.5 | Patamar de escada | Maciça | 0 | 11 | Externo | 154.5 | 300 | Patamar de escada C-25 - h=11cm
LE7 | Arquibancada | LANDING | 2.5 | Patamar de escada | Maciça | 12 | 12 | Externo | 0 | 0 | Patamar de escada C-25 - h=12cm
LE9 | Arquibancada | LANDING | 2.5 | Patamar de escada | Maciça | 0 | 11 | Externo | 154.5 | 400 | Patamar de escada C-25 - h=11cm
L1 | Respalto | FLOOR | 2.5 | Laje | Pré-moldada | 0 | 12 | Externo | 50 | 50 | Laje Pré-moldada - h=12cm
L2 | Respalto | FLOOR | 2.5 | Laje | Pré-moldada | 0 | 12 | Externo | 50 | 50 | Laje Pré-moldada - h=12cm
L3 | Respalto | FLOOR | 2.5 | Laje | Pré-moldada | 0 | 12 | Externo | 50 | 50 | Laje Pré-moldada - h=12cm

# IfcStairFlight (16)
In: Arquibancada
NumberOfRisers: 0; NumberOfTreads: 0; Material: Concreto
Pset_ConcreteElementGeneral - ConcreteCover: 3 cm; ConstructionMethod: InSitu; ExposureClass: 2; StrengthClass: C-25
AltoQi_Eberick_Elemento - Elemento: Escada; Tipo: Fundo plano; Espessura: 11 cm; Piso: 27 cm; Espelho: 17 cm; Primeira_face: 0 cm
AltoQi_Eberick_Padrão - Ambiente: Contato com solo; Cobrimento: 3 cm; Classe de concreto: C-25
AltoQi_Eberick_Cargas - Revestimento (G2): 154.5; Adicional (G2): 0; Solo (S): 0; Acidental (Q): 300; Água (A): 0; Subpressão (AS): 0
Pset_StairFlightCommon - Reference: Lance de escada C-25 - Fundo plano - h= 11cm; RiserHeight: 17 cm; TreadLength: 27 cm; WaistThickness: 11 cm
Name
LE14
LE15
LE16
LE17
LE20
LE22
LE27
LE33
LE41
LE42
LE43
LE51
LE53
LE55
LE57
LE58
